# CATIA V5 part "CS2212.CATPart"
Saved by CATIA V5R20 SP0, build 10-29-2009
Part number: CS2212
Revision: 6
Definition: design
Nomenclature: CS2212
Source: made
Description: NOT SPECIFIED
Bounding box of the stored display mesh (mm): x -11.818 to 12, y -12 to 12, z -22 to 6
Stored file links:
  C:\Users\Raffaele\Desktop\3D X SITO CF\BOLEX\20-TILTED COLUMN SUPPORT\CS2212.CATPart

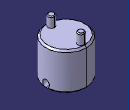
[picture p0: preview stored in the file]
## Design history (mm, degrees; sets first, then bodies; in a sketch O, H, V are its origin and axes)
Body1 "MANIFOLD_SOLID_BREP #716" (main body)
  Solid1: solid without history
